VERSION 5.7 ;
  NOWIREEXTENSIONATPIN ON ;
  DIVIDERCHAR "/" ;
  BUSBITCHARS "[]" ;
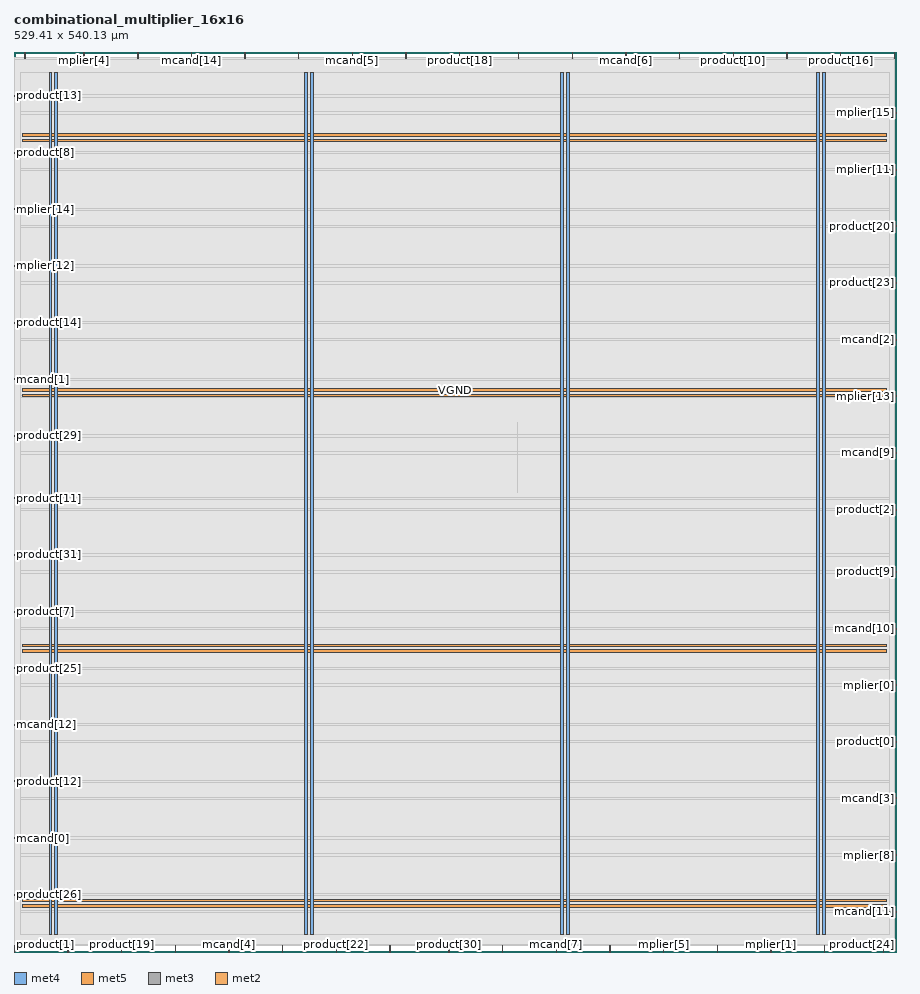
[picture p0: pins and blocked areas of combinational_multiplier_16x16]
MACRO combinational_multiplier_16x16
  CLASS BLOCK ;
  FOREIGN combinational_multiplier_16x16 ;
  ORIGIN 0.000 0.000 ;
  SIZE 529.410 BY 540.130 ;
  PIN VGND
    DIRECTION INOUT ;
    USE GROUND ;
    PORT
      LAYER met4 ;
        RECT 24.340 10.640 25.940 527.920 ;
    END
    PORT
      LAYER met4 ;
        RECT 177.940 10.640 179.540 527.920 ;
    END
    PORT
      LAYER met4 ;
        RECT 331.540 10.640 333.140 527.920 ;
    END
    PORT
      LAYER met4 ;
        RECT 485.140 10.640 486.740 527.920 ;
    END
    PORT
      LAYER met5 ;
        RECT 5.280 30.030 523.720 31.630 ;
    END
    PORT
      LAYER met5 ;
        RECT 5.280 183.210 523.720 184.810 ;
    END
    PORT
      LAYER met5 ;
        RECT 5.280 336.390 523.720 337.990 ;
    END
    PORT
      LAYER met5 ;
        RECT 5.280 489.570 523.720 491.170 ;
    END
  END VGND
  PIN VPWR
    DIRECTION INOUT ;
    USE POWER ;
    PORT
      LAYER met4 ;
        RECT 21.040 10.640 22.640 527.920 ;
    END
    PORT
      LAYER met4 ;
        RECT 174.640 10.640 176.240 527.920 ;
    END
    PORT
      LAYER met4 ;
        RECT 328.240 10.640 329.840 527.920 ;
    END
    PORT
      LAYER met4 ;
        RECT 481.840 10.640 483.440 527.920 ;
    END
    PORT
      LAYER met5 ;
        RECT 5.280 26.730 523.720 28.330 ;
    END
    PORT
      LAYER met5 ;
        RECT 5.280 179.910 523.720 181.510 ;
    END
    PORT
      LAYER met5 ;
        RECT 5.280 333.090 523.720 334.690 ;
    END
    PORT
      LAYER met5 ;
        RECT 5.280 486.270 523.720 487.870 ;
    END
  END VPWR
  PIN mcand[0]
    DIRECTION INPUT ;
    USE SIGNAL ;
    ANTENNAGATEAREA 0.742500 ;
    PORT
      LAYER met3 ;
        RECT 0.000 68.040 4.000 68.640 ;
    END
  END mcand[0]
  PIN mcand[10]
    DIRECTION INPUT ;
    USE SIGNAL ;
    ANTENNAGATEAREA 0.247500 ;
    PORT
      LAYER met3 ;
        RECT 525.410 193.840 529.410 194.440 ;
    END
  END mcand[10]
  PIN mcand[11]
    DIRECTION INPUT ;
    USE SIGNAL ;
    ANTENNAGATEAREA 0.742500 ;
    PORT
      LAYER met3 ;
        RECT 525.410 23.840 529.410 24.440 ;
    END
  END mcand[11]
  PIN mcand[12]
    DIRECTION INPUT ;
    USE SIGNAL ;
    ANTENNAGATEAREA 0.426000 ;
    PORT
      LAYER met3 ;
        RECT 0.000 136.040 4.000 136.640 ;
    END
  END mcand[12]
  PIN mcand[13]
    DIRECTION INPUT ;
    USE SIGNAL ;
    ANTENNAGATEAREA 0.213000 ;
    PORT
      LAYER met2 ;
        RECT 235.150 536.130 235.430 540.130 ;
    END
  END mcand[13]
  PIN mcand[14]
    DIRECTION INPUT ;
    USE SIGNAL ;
    ANTENNAGATEAREA 0.247500 ;
    PORT
      LAYER met2 ;
        RECT 106.350 536.130 106.630 540.130 ;
    END
  END mcand[14]
  PIN mcand[15]
    DIRECTION INPUT ;
    USE SIGNAL ;
    ANTENNAGATEAREA 0.247500 ;
    PORT
      LAYER met2 ;
        RECT 6.530 536.130 6.810 540.130 ;
    END
  END mcand[15]
  PIN mcand[1]
    DIRECTION INPUT ;
    USE SIGNAL ;
    ANTENNAGATEAREA 0.990000 ;
    PORT
      LAYER met3 ;
        RECT 0.000 343.440 4.000 344.040 ;
    END
  END mcand[1]
  PIN mcand[2]
    DIRECTION INPUT ;
    USE SIGNAL ;
    ANTENNAGATEAREA 0.247500 ;
    PORT
      LAYER met3 ;
        RECT 525.410 367.240 529.410 367.840 ;
    END
  END mcand[2]
  PIN mcand[3]
    DIRECTION INPUT ;
    USE SIGNAL ;
    ANTENNAGATEAREA 0.247500 ;
    PORT
      LAYER met3 ;
        RECT 525.410 91.840 529.410 92.440 ;
    END
  END mcand[3]
  PIN mcand[4]
    DIRECTION INPUT ;
    USE SIGNAL ;
    ANTENNAGATEAREA 0.213000 ;
    PORT
      LAYER met2 ;
        RECT 128.890 0.000 129.170 4.000 ;
    END
  END mcand[4]
  PIN mcand[5]
    DIRECTION INPUT ;
    USE SIGNAL ;
    ANTENNAGATEAREA 0.247500 ;
    PORT
      LAYER met2 ;
        RECT 202.950 536.130 203.230 540.130 ;
    END
  END mcand[5]
  PIN mcand[6]
    DIRECTION INPUT ;
    USE SIGNAL ;
    ANTENNAGATEAREA 0.247500 ;
    PORT
      LAYER met2 ;
        RECT 367.170 536.130 367.450 540.130 ;
    END
  END mcand[6]
  PIN mcand[7]
    DIRECTION INPUT ;
    USE SIGNAL ;
    ANTENNAGATEAREA 0.159000 ;
    PORT
      LAYER met2 ;
        RECT 325.310 0.000 325.590 4.000 ;
    END
  END mcand[7]
  PIN mcand[8]
    DIRECTION INPUT ;
    USE SIGNAL ;
    ANTENNAGATEAREA 0.247500 ;
    PORT
      LAYER met2 ;
        RECT 32.290 0.000 32.570 4.000 ;
    END
  END mcand[8]
  PIN mcand[9]
    DIRECTION INPUT ;
    USE SIGNAL ;
    ANTENNAGATEAREA 0.247500 ;
    PORT
      LAYER met3 ;
        RECT 525.410 299.240 529.410 299.840 ;
    END
  END mcand[9]
  PIN mplier[0]
    DIRECTION INPUT ;
    USE SIGNAL ;
    ANTENNAGATEAREA 0.213000 ;
    PORT
      LAYER met3 ;
        RECT 525.410 159.840 529.410 160.440 ;
    END
  END mplier[0]
  PIN mplier[10]
    DIRECTION INPUT ;
    USE SIGNAL ;
    ANTENNAGATEAREA 0.159000 ;
    PORT
      LAYER met2 ;
        RECT 302.770 536.130 303.050 540.130 ;
    END
  END mplier[10]
  PIN mplier[11]
    DIRECTION INPUT ;
    USE SIGNAL ;
    ANTENNAGATEAREA 0.247500 ;
    PORT
      LAYER met3 ;
        RECT 525.410 469.240 529.410 469.840 ;
    END
  END mplier[11]
  PIN mplier[12]
    DIRECTION INPUT ;
    USE SIGNAL ;
    ANTENNAGATEAREA 0.213000 ;
    PORT
      LAYER met3 ;
        RECT 0.000 411.440 4.000 412.040 ;
    END
  END mplier[12]
  PIN mplier[13]
    DIRECTION INPUT ;
    USE SIGNAL ;
    ANTENNAGATEAREA 0.213000 ;
    PORT
      LAYER met3 ;
        RECT 525.410 333.240 529.410 333.840 ;
    END
  END mplier[13]
  PIN mplier[14]
    DIRECTION INPUT ;
    USE SIGNAL ;
    ANTENNAGATEAREA 0.426000 ;
    PORT
      LAYER met3 ;
        RECT 0.000 445.440 4.000 446.040 ;
    END
  END mplier[14]
  PIN mplier[15]
    DIRECTION INPUT ;
    USE SIGNAL ;
    ANTENNAGATEAREA 0.426000 ;
    PORT
      LAYER met3 ;
        RECT 525.410 503.240 529.410 503.840 ;
    END
  END mplier[15]
  PIN mplier[1]
    DIRECTION INPUT ;
    USE SIGNAL ;
    ANTENNAGATEAREA 0.213000 ;
    PORT
      LAYER met2 ;
        RECT 454.110 0.000 454.390 4.000 ;
    END
  END mplier[1]
  PIN mplier[2]
    DIRECTION INPUT ;
    USE SIGNAL ;
    ANTENNAGATEAREA 0.495000 ;
    PORT
      LAYER met2 ;
        RECT 421.910 0.000 422.190 4.000 ;
    END
  END mplier[2]
  PIN mplier[3]
    DIRECTION INPUT ;
    USE SIGNAL ;
    ANTENNAGATEAREA 0.247500 ;
    PORT
      LAYER met2 ;
        RECT 225.490 0.000 225.770 4.000 ;
    END
  END mplier[3]
  PIN mplier[4]
    DIRECTION INPUT ;
    USE SIGNAL ;
    ANTENNAGATEAREA 0.495000 ;
    PORT
      LAYER met2 ;
        RECT 41.950 536.130 42.230 540.130 ;
    END
  END mplier[4]
  PIN mplier[5]
    DIRECTION INPUT ;
    USE SIGNAL ;
    ANTENNAGATEAREA 0.247500 ;
    PORT
      LAYER met2 ;
        RECT 389.710 0.000 389.990 4.000 ;
    END
  END mplier[5]
  PIN mplier[6]
    DIRECTION INPUT ;
    USE SIGNAL ;
    ANTENNAGATEAREA 0.213000 ;
    PORT
      LAYER met2 ;
        RECT 334.970 536.130 335.250 540.130 ;
    END
  END mplier[6]
  PIN mplier[7]
    DIRECTION INPUT ;
    USE SIGNAL ;
    ANTENNAGATEAREA 0.247500 ;
    PORT
      LAYER met2 ;
        RECT 486.310 0.000 486.590 4.000 ;
    END
  END mplier[7]
  PIN mplier[8]
    DIRECTION INPUT ;
    USE SIGNAL ;
    ANTENNAGATEAREA 0.247500 ;
    PORT
      LAYER met3 ;
        RECT 525.410 57.840 529.410 58.440 ;
    END
  END mplier[8]
  PIN mplier[9]
    DIRECTION INPUT ;
    USE SIGNAL ;
    ANTENNAGATEAREA 0.159000 ;
    PORT
      LAYER met2 ;
        RECT 293.110 0.000 293.390 4.000 ;
    END
  END mplier[9]
  PIN product[0]
    DIRECTION OUTPUT TRISTATE ;
    USE SIGNAL ;
    ANTENNADIFFAREA 0.445500 ;
    PORT
      LAYER met3 ;
        RECT 525.410 125.840 529.410 126.440 ;
    END
  END product[0]
  PIN product[10]
    DIRECTION OUTPUT TRISTATE ;
    USE SIGNAL ;
    ANTENNADIFFAREA 0.795200 ;
    PORT
      LAYER met2 ;
        RECT 431.570 536.130 431.850 540.130 ;
    END
  END product[10]
  PIN product[11]
    DIRECTION OUTPUT TRISTATE ;
    USE SIGNAL ;
    ANTENNADIFFAREA 0.795200 ;
    PORT
      LAYER met3 ;
        RECT 0.000 272.040 4.000 272.640 ;
    END
  END product[11]
  PIN product[12]
    DIRECTION OUTPUT TRISTATE ;
    USE SIGNAL ;
    ANTENNADIFFAREA 0.795200 ;
    PORT
      LAYER met3 ;
        RECT 0.000 102.040 4.000 102.640 ;
    END
  END product[12]
  PIN product[13]
    DIRECTION OUTPUT TRISTATE ;
    USE SIGNAL ;
    ANTENNADIFFAREA 0.795200 ;
    PORT
      LAYER met3 ;
        RECT 0.000 513.440 4.000 514.040 ;
    END
  END product[13]
  PIN product[14]
    DIRECTION OUTPUT TRISTATE ;
    USE SIGNAL ;
    ANTENNADIFFAREA 0.795200 ;
    PORT
      LAYER met3 ;
        RECT 0.000 377.440 4.000 378.040 ;
    END
  END product[14]
  PIN product[15]
    DIRECTION OUTPUT TRISTATE ;
    USE SIGNAL ;
    ANTENNADIFFAREA 0.795200 ;
    PORT
      LAYER met2 ;
        RECT 399.370 536.130 399.650 540.130 ;
    END
  END product[15]
  PIN product[16]
    DIRECTION OUTPUT TRISTATE ;
    USE SIGNAL ;
    ANTENNADIFFAREA 0.795200 ;
    PORT
      LAYER met2 ;
        RECT 495.970 536.130 496.250 540.130 ;
    END
  END product[16]
  PIN product[17]
    DIRECTION OUTPUT TRISTATE ;
    USE SIGNAL ;
    ANTENNADIFFAREA 0.795200 ;
    PORT
      LAYER met2 ;
        RECT 138.550 536.130 138.830 540.130 ;
    END
  END product[17]
  PIN product[18]
    DIRECTION OUTPUT TRISTATE ;
    USE SIGNAL ;
    ANTENNADIFFAREA 0.795200 ;
    PORT
      LAYER met2 ;
        RECT 267.350 536.130 267.630 540.130 ;
    END
  END product[18]
  PIN product[19]
    DIRECTION OUTPUT TRISTATE ;
    USE SIGNAL ;
    ANTENNADIFFAREA 0.795200 ;
    PORT
      LAYER met2 ;
        RECT 64.490 0.000 64.770 4.000 ;
    END
  END product[19]
  PIN product[1]
    DIRECTION OUTPUT TRISTATE ;
    USE SIGNAL ;
    ANTENNADIFFAREA 0.795200 ;
    PORT
      LAYER met2 ;
        RECT 0.090 0.000 0.370 4.000 ;
    END
  END product[1]
  PIN product[20]
    DIRECTION OUTPUT TRISTATE ;
    USE SIGNAL ;
    ANTENNADIFFAREA 0.445500 ;
    PORT
      LAYER met3 ;
        RECT 525.410 435.240 529.410 435.840 ;
    END
  END product[20]
  PIN product[21]
    DIRECTION OUTPUT TRISTATE ;
    USE SIGNAL ;
    ANTENNADIFFAREA 0.795200 ;
    PORT
      LAYER met2 ;
        RECT 528.170 536.130 528.450 540.130 ;
    END
  END product[21]
  PIN product[22]
    DIRECTION OUTPUT TRISTATE ;
    USE SIGNAL ;
    ANTENNADIFFAREA 0.795200 ;
    PORT
      LAYER met2 ;
        RECT 193.290 0.000 193.570 4.000 ;
    END
  END product[22]
  PIN product[23]
    DIRECTION OUTPUT TRISTATE ;
    USE SIGNAL ;
    ANTENNADIFFAREA 0.445500 ;
    PORT
      LAYER met3 ;
        RECT 525.410 401.240 529.410 401.840 ;
    END
  END product[23]
  PIN product[24]
    DIRECTION OUTPUT TRISTATE ;
    USE SIGNAL ;
    ANTENNADIFFAREA 0.795200 ;
    PORT
      LAYER met2 ;
        RECT 521.730 0.000 522.010 4.000 ;
    END
  END product[24]
  PIN product[25]
    DIRECTION OUTPUT TRISTATE ;
    USE SIGNAL ;
    ANTENNADIFFAREA 0.795200 ;
    PORT
      LAYER met3 ;
        RECT 0.000 170.040 4.000 170.640 ;
    END
  END product[25]
  PIN product[26]
    DIRECTION OUTPUT TRISTATE ;
    USE SIGNAL ;
    ANTENNADIFFAREA 0.795200 ;
    PORT
      LAYER met3 ;
        RECT 0.000 34.040 4.000 34.640 ;
    END
  END product[26]
  PIN product[27]
    DIRECTION OUTPUT TRISTATE ;
    USE SIGNAL ;
    ANTENNADIFFAREA 0.795200 ;
    PORT
      LAYER met2 ;
        RECT 96.690 0.000 96.970 4.000 ;
    END
  END product[27]
  PIN product[28]
    DIRECTION OUTPUT TRISTATE ;
    USE SIGNAL ;
    ANTENNADIFFAREA 0.795200 ;
    PORT
      LAYER met2 ;
        RECT 161.090 0.000 161.370 4.000 ;
    END
  END product[28]
  PIN product[29]
    DIRECTION OUTPUT TRISTATE ;
    USE SIGNAL ;
    ANTENNADIFFAREA 0.795200 ;
    PORT
      LAYER met3 ;
        RECT 0.000 309.440 4.000 310.040 ;
    END
  END product[29]
  PIN product[2]
    DIRECTION OUTPUT TRISTATE ;
    USE SIGNAL ;
    ANTENNADIFFAREA 0.445500 ;
    PORT
      LAYER met3 ;
        RECT 525.410 265.240 529.410 265.840 ;
    END
  END product[2]
  PIN product[30]
    DIRECTION OUTPUT TRISTATE ;
    USE SIGNAL ;
    ANTENNADIFFAREA 1.336500 ;
    PORT
      LAYER met2 ;
        RECT 260.910 0.000 261.190 4.000 ;
    END
  END product[30]
  PIN product[31]
    DIRECTION OUTPUT TRISTATE ;
    USE SIGNAL ;
    ANTENNADIFFAREA 0.795200 ;
    PORT
      LAYER met3 ;
        RECT 0.000 238.040 4.000 238.640 ;
    END
  END product[31]
  PIN product[3]
    DIRECTION OUTPUT TRISTATE ;
    USE SIGNAL ;
    ANTENNADIFFAREA 0.445500 ;
    PORT
      LAYER met2 ;
        RECT 463.770 536.130 464.050 540.130 ;
    END
  END product[3]
  PIN product[4]
    DIRECTION OUTPUT TRISTATE ;
    USE SIGNAL ;
    ANTENNADIFFAREA 0.795200 ;
    PORT
      LAYER met2 ;
        RECT 74.150 536.130 74.430 540.130 ;
    END
  END product[4]
  PIN product[5]
    DIRECTION OUTPUT TRISTATE ;
    USE SIGNAL ;
    ANTENNADIFFAREA 0.795200 ;
    PORT
      LAYER met2 ;
        RECT 170.750 536.130 171.030 540.130 ;
    END
  END product[5]
  PIN product[6]
    DIRECTION OUTPUT TRISTATE ;
    USE SIGNAL ;
    ANTENNADIFFAREA 0.795200 ;
    PORT
      LAYER met2 ;
        RECT 357.510 0.000 357.790 4.000 ;
    END
  END product[6]
  PIN product[7]
    DIRECTION OUTPUT TRISTATE ;
    USE SIGNAL ;
    ANTENNADIFFAREA 0.795200 ;
    PORT
      LAYER met3 ;
        RECT 0.000 204.040 4.000 204.640 ;
    END
  END product[7]
  PIN product[8]
    DIRECTION OUTPUT TRISTATE ;
    USE SIGNAL ;
    ANTENNADIFFAREA 0.795200 ;
    PORT
      LAYER met3 ;
        RECT 0.000 479.440 4.000 480.040 ;
    END
  END product[8]
  PIN product[9]
    DIRECTION OUTPUT TRISTATE ;
    USE SIGNAL ;
    ANTENNADIFFAREA 0.445500 ;
    PORT
      LAYER met3 ;
        RECT 525.410 227.840 529.410 228.440 ;
    END
  END product[9]
  OBS
      LAYER li1 ;
        RECT 5.520 10.795 523.480 527.765 ;
      LAYER met1 ;
        RECT 0.070 7.860 528.470 528.660 ;
      LAYER met2 ;
        RECT 0.100 535.850 6.250 536.930 ;
        RECT 7.090 535.850 41.670 536.930 ;
        RECT 42.510 535.850 73.870 536.930 ;
        RECT 74.710 535.850 106.070 536.930 ;
        RECT 106.910 535.850 138.270 536.930 ;
        RECT 139.110 535.850 170.470 536.930 ;
        RECT 171.310 535.850 202.670 536.930 ;
        RECT 203.510 535.850 234.870 536.930 ;
        RECT 235.710 535.850 267.070 536.930 ;
        RECT 267.910 535.850 302.490 536.930 ;
        RECT 303.330 535.850 334.690 536.930 ;
        RECT 335.530 535.850 366.890 536.930 ;
        RECT 367.730 535.850 399.090 536.930 ;
        RECT 399.930 535.850 431.290 536.930 ;
        RECT 432.130 535.850 463.490 536.930 ;
        RECT 464.330 535.850 495.690 536.930 ;
        RECT 496.530 535.850 527.890 536.930 ;
        RECT 0.100 4.280 528.440 535.850 ;
        RECT 0.650 4.000 32.010 4.280 ;
        RECT 32.850 4.000 64.210 4.280 ;
        RECT 65.050 4.000 96.410 4.280 ;
        RECT 97.250 4.000 128.610 4.280 ;
        RECT 129.450 4.000 160.810 4.280 ;
        RECT 161.650 4.000 193.010 4.280 ;
        RECT 193.850 4.000 225.210 4.280 ;
        RECT 226.050 4.000 260.630 4.280 ;
        RECT 261.470 4.000 292.830 4.280 ;
        RECT 293.670 4.000 325.030 4.280 ;
        RECT 325.870 4.000 357.230 4.280 ;
        RECT 358.070 4.000 389.430 4.280 ;
        RECT 390.270 4.000 421.630 4.280 ;
        RECT 422.470 4.000 453.830 4.280 ;
        RECT 454.670 4.000 486.030 4.280 ;
        RECT 486.870 4.000 521.450 4.280 ;
        RECT 522.290 4.000 528.440 4.280 ;
      LAYER met3 ;
        RECT 3.990 514.440 525.410 527.845 ;
        RECT 4.400 513.040 525.410 514.440 ;
        RECT 3.990 504.240 525.410 513.040 ;
        RECT 3.990 502.840 525.010 504.240 ;
        RECT 3.990 480.440 525.410 502.840 ;
        RECT 4.400 479.040 525.410 480.440 ;
        RECT 3.990 470.240 525.410 479.040 ;
        RECT 3.990 468.840 525.010 470.240 ;
        RECT 3.990 446.440 525.410 468.840 ;
        RECT 4.400 445.040 525.410 446.440 ;
        RECT 3.990 436.240 525.410 445.040 ;
        RECT 3.990 434.840 525.010 436.240 ;
        RECT 3.990 412.440 525.410 434.840 ;
        RECT 4.400 411.040 525.410 412.440 ;
        RECT 3.990 402.240 525.410 411.040 ;
        RECT 3.990 400.840 525.010 402.240 ;
        RECT 3.990 378.440 525.410 400.840 ;
        RECT 4.400 377.040 525.410 378.440 ;
        RECT 3.990 368.240 525.410 377.040 ;
        RECT 3.990 366.840 525.010 368.240 ;
        RECT 3.990 344.440 525.410 366.840 ;
        RECT 4.400 343.040 525.410 344.440 ;
        RECT 3.990 334.240 525.410 343.040 ;
        RECT 3.990 332.840 525.010 334.240 ;
        RECT 3.990 310.440 525.410 332.840 ;
        RECT 4.400 309.040 525.410 310.440 ;
        RECT 3.990 300.240 525.410 309.040 ;
        RECT 3.990 298.840 525.010 300.240 ;
        RECT 3.990 273.040 525.410 298.840 ;
        RECT 4.400 271.640 525.410 273.040 ;
        RECT 3.990 266.240 525.410 271.640 ;
        RECT 3.990 264.840 525.010 266.240 ;
        RECT 3.990 239.040 525.410 264.840 ;
        RECT 4.400 237.640 525.410 239.040 ;
        RECT 3.990 228.840 525.410 237.640 ;
        RECT 3.990 227.440 525.010 228.840 ;
        RECT 3.990 205.040 525.410 227.440 ;
        RECT 4.400 203.640 525.410 205.040 ;
        RECT 3.990 194.840 525.410 203.640 ;
        RECT 3.990 193.440 525.010 194.840 ;
        RECT 3.990 171.040 525.410 193.440 ;
        RECT 4.400 169.640 525.410 171.040 ;
        RECT 3.990 160.840 525.410 169.640 ;
        RECT 3.990 159.440 525.010 160.840 ;
        RECT 3.990 137.040 525.410 159.440 ;
        RECT 4.400 135.640 525.410 137.040 ;
        RECT 3.990 126.840 525.410 135.640 ;
        RECT 3.990 125.440 525.010 126.840 ;
        RECT 3.990 103.040 525.410 125.440 ;
        RECT 4.400 101.640 525.410 103.040 ;
        RECT 3.990 92.840 525.410 101.640 ;
        RECT 3.990 91.440 525.010 92.840 ;
        RECT 3.990 69.040 525.410 91.440 ;
        RECT 4.400 67.640 525.410 69.040 ;
        RECT 3.990 58.840 525.410 67.640 ;
        RECT 3.990 57.440 525.010 58.840 ;
        RECT 3.990 35.040 525.410 57.440 ;
        RECT 4.400 33.640 525.410 35.040 ;
        RECT 3.990 24.840 525.410 33.640 ;
        RECT 3.990 23.440 525.010 24.840 ;
        RECT 3.990 10.715 525.410 23.440 ;
      LAYER met4 ;
        RECT 302.055 275.575 302.385 318.065 ;
  END
END combinational_multiplier_16x16
END LIBRARY

